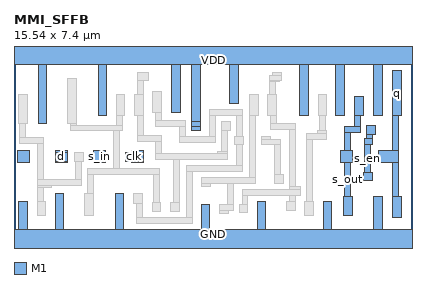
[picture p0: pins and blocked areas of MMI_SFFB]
MACRO MMI_SFFB
	CLASS CORE ;
	FOREIGN MMI_SFFB 0 0 ;
	SIZE 15.54 BY 7.4 ;
	SYMMETRY X Y ;
	SITE CORE1 ;
	PIN d
		DIRECTION input ;
		USE SIGNAL ;
		PORT
			LAYER M1 ;
			RECT 1.625 3.485 2.075 3.555 ;
			LAYER M1 ;
			RECT 1.61 3.145 2.075 3.485 ;
			LAYER M1 ;
			RECT 1.625 3.105 2.075 3.145 ;
		END
		AntennaGateArea 0.4968 ;
	END d
	PIN GND
		DIRECTION inout ;
		USE GROUND ;
		PORT
			LAYER M1 ;
			RECT 0.18 0.5 0.52 1.57 ;
			LAYER M1 ;
			RECT 1.6 0.5 1.94 1.88 ;
			LAYER M1 ;
			RECT 3.94 0.5 4.28 1.88 ;
			LAYER M1 ;
			RECT 7.29 0.5 7.63 1.48 ;
			LAYER M1 ;
			RECT 9.47 0.5 9.81 1.57 ;
			LAYER M1 ;
			RECT 12.04 0.5 12.38 1.57 ;
			LAYER M1 ;
			RECT 14.02 0.5 14.36 1.79 ;
			LAYER M1 ;
			RECT 0 -0.5 15.54 0.5 ;
		END
	END GND
	PIN q
		DIRECTION output ;
		USE SIGNAL ;
		PORT
			LAYER M1 ;
			RECT 14.74 4.91 15.08 6.67 ;
			LAYER M1 ;
			RECT 14.74 3.555 14.97 4.91 ;
			LAYER M1 ;
			RECT 14.205 3.105 14.97 3.555 ;
			LAYER M1 ;
			RECT 14.74 1.79 14.97 3.105 ;
			LAYER M1 ;
			RECT 14.74 0.95 15.08 1.79 ;
		END
		AntennaDiffArea 1.3248 ;
	END q
	PIN s_in
		DIRECTION input ;
		USE SIGNAL ;
		PORT
			LAYER M1 ;
			RECT 3.105 3.105 3.555 3.555 ;
		END
		AntennaGateArea 0.2484 ;
	END s_in
	PIN s_en
		DIRECTION input ;
		USE SIGNAL ;
		PORT
			LAYER M1 ;
			RECT 13.74 4.18 14.08 4.52 ;
			LAYER M1 ;
			RECT 13.74 4.02 13.97 4.18 ;
			LAYER M1 ;
			RECT 13.66 3.79 13.97 4.02 ;
			LAYER M1 ;
			RECT 0.145 3.105 0.595 3.555 ;
			LAYER M1 ;
			RECT 13.66 2.72 13.89 3.79 ;
			LAYER M1 ;
			RECT 13.62 2.38 13.96 2.72 ;
		END
		AntennaGateArea 1.0404 ;
	END s_en
	PIN VDD
		DIRECTION inout ;
		USE POWER ;
		PORT
			LAYER M1 ;
			RECT 0 6.9 15.54 7.9 ;
			LAYER M1 ;
			RECT 0.94 4.61 1.28 6.9 ;
			LAYER M1 ;
			RECT 3.28 4.91 3.62 6.9 ;
			LAYER M1 ;
			RECT 6.13 5.03 6.47 6.9 ;
			LAYER M1 ;
			RECT 6.925 4.69 7.265 6.9 ;
			LAYER M1 ;
			RECT 8.405 5.38 8.745 6.9 ;
			LAYER M1 ;
			RECT 11.12 4.91 11.46 6.9 ;
			LAYER M1 ;
			RECT 12.54 4.91 12.88 6.9 ;
			LAYER M1 ;
			RECT 14.02 4.91 14.36 6.9 ;
			LAYER M1 ;
			RECT 6.925 4.515 7.27 4.69 ;
			LAYER M1 ;
			RECT 6.93 4.35 7.27 4.515 ;
		END
	END VDD
	PIN s_out
		DIRECTION output ;
		USE SIGNAL ;
		PORT
			LAYER M1 ;
			RECT 13.26 4.91 13.6 5.67 ;
			LAYER M1 ;
			RECT 13.26 4.495 13.49 4.91 ;
			LAYER M1 ;
			RECT 12.865 4.265 13.49 4.495 ;
			LAYER M1 ;
			RECT 12.865 3.555 13.095 4.265 ;
			LAYER M1 ;
			RECT 12.725 3.105 13.175 3.555 ;
			LAYER M1 ;
			RECT 12.865 1.79 13.095 3.105 ;
			LAYER M1 ;
			RECT 12.83 1.03 13.17 1.79 ;
		END
		AntennaDiffArea 0.8568 ;
	END s_out
	PIN clk
		DIRECTION input ;
		USE CLOCK ;
		PORT
			LAYER M1 ;
			RECT 4.585 3.49 5.035 3.555 ;
			LAYER M1 ;
			RECT 4.34 3.15 5.035 3.49 ;
			LAYER M1 ;
			RECT 4.585 3.105 5.035 3.15 ;
		END
		AntennaGateArea 0.6408 ;
	END clk
	OBS
		LAYER M1 ;
		RECT 0.18 4.61 0.52 5.73 ;
		LAYER M1 ;
		RECT 2.09 4.61 2.43 6.37 ;
		LAYER M1 ;
		RECT 4.81 6.275 5.23 6.615 ;
		LAYER M1 ;
		RECT 4.81 5.75 5.04 6.275 ;
		LAYER M1 ;
		RECT 3.98 4.91 4.32 5.75 ;
		LAYER M1 ;
		RECT 4.7 4.91 5.04 5.75 ;
		LAYER M1 ;
		RECT 5.41 5.03 5.75 5.87 ;
		LAYER M1 ;
		RECT 0.215 4.07 0.445 4.61 ;
		LAYER M1 ;
		RECT 2.2 4.555 2.43 4.61 ;
		LAYER M1 ;
		RECT 3.98 4.555 4.21 4.91 ;
		LAYER M1 ;
		RECT 2.2 4.325 4.21 4.555 ;
		LAYER M1 ;
		RECT 0.215 3.84 1.13 4.07 ;
		LAYER M1 ;
		RECT 0.9 2.45 1.13 3.84 ;
		LAYER M1 ;
		RECT 2.37 3.145 2.71 3.485 ;
		LAYER M1 ;
		RECT 2.38 2.45 2.61 3.145 ;
		LAYER M1 ;
		RECT 3.865 2.875 4.095 4.325 ;
		LAYER M1 ;
		RECT 4.81 4.14 5.04 4.91 ;
		LAYER M1 ;
		RECT 5.52 4.73 5.75 5.03 ;
		LAYER M1 ;
		RECT 5.52 4.5 6.68 4.73 ;
		LAYER M1 ;
		RECT 10.08 6.475 10.42 6.62 ;
		LAYER M1 ;
		RECT 9.955 6.28 10.42 6.475 ;
		LAYER M1 ;
		RECT 9.955 6.245 10.35 6.28 ;
		LAYER M1 ;
		RECT 9.955 5.75 10.185 6.245 ;
		LAYER M1 ;
		RECT 7.61 4.92 8.88 5.15 ;
		LAYER M1 ;
		RECT 4.81 3.91 5.73 4.14 ;
		LAYER M1 ;
		RECT 5.5 3.43 5.73 3.91 ;
		LAYER M1 ;
		RECT 6.45 4.12 6.68 4.5 ;
		LAYER M1 ;
		RECT 7.61 4.12 7.84 4.92 ;
		LAYER M1 ;
		RECT 6.45 3.89 7.84 4.12 ;
		LAYER M1 ;
		RECT 8.08 4.35 8.42 4.69 ;
		LAYER M1 ;
		RECT 8.08 3.54 8.31 4.35 ;
		LAYER M1 ;
		RECT 8.65 4.12 8.88 4.92 ;
		LAYER M1 ;
		RECT 9.17 4.91 9.51 5.75 ;
		LAYER M1 ;
		RECT 9.89 4.91 10.23 5.75 ;
		LAYER M1 ;
		RECT 11.84 4.91 12.18 5.75 ;
		LAYER M1 ;
		RECT 8.6 3.78 8.94 4.12 ;
		LAYER M1 ;
		RECT 7.93 3.43 8.31 3.54 ;
		LAYER M1 ;
		RECT 5.5 3.2 8.31 3.43 ;
		LAYER M1 ;
		RECT 0.9 2.22 2.61 2.45 ;
		LAYER M1 ;
		RECT 2.86 2.645 5.65 2.875 ;
		LAYER M1 ;
		RECT 0.9 2.11 1.455 2.22 ;
		LAYER M1 ;
		RECT 0.9 1.57 1.13 2.11 ;
		LAYER M1 ;
		RECT 2.86 1.88 3.09 2.645 ;
		LAYER M1 ;
		RECT 0.9 1.05 1.24 1.57 ;
		LAYER M1 ;
		RECT 2.75 1.04 3.09 1.88 ;
		LAYER M1 ;
		RECT 4.66 1.5 5 1.88 ;
		LAYER M1 ;
		RECT 5.42 1.53 5.65 2.645 ;
		LAYER M1 ;
		RECT 6.21 1.53 6.44 3.2 ;
		LAYER M1 ;
		RECT 8.65 2.97 8.88 3.78 ;
		LAYER M1 ;
		RECT 4.77 0.96 5 1.5 ;
		LAYER M1 ;
		RECT 5.38 1.19 5.72 1.53 ;
		LAYER M1 ;
		RECT 6.1 1.19 6.44 1.53 ;
		LAYER M1 ;
		RECT 6.73 2.74 8.88 2.97 ;
		LAYER M1 ;
		RECT 6.73 0.96 6.96 2.74 ;
		LAYER M1 ;
		RECT 9.17 2.5 9.4 4.91 ;
		LAYER M1 ;
		RECT 10 4.6 10.23 4.91 ;
		LAYER M1 ;
		RECT 10 4.37 10.96 4.6 ;
		LAYER M1 ;
		RECT 9.65 4.01 9.99 4.12 ;
		LAYER M1 ;
		RECT 9.65 3.78 10.37 4.01 ;
		LAYER M1 ;
		RECT 7.32 2.27 9.4 2.5 ;
		LAYER M1 ;
		RECT 10.14 2.61 10.37 3.78 ;
		LAYER M1 ;
		RECT 10.14 2.27 10.48 2.61 ;
		LAYER M1 ;
		RECT 7.32 2.16 7.66 2.27 ;
		LAYER M1 ;
		RECT 8.31 1.48 8.54 2.27 ;
		LAYER M1 ;
		RECT 10.73 2.15 10.96 4.37 ;
		LAYER M1 ;
		RECT 11.89 4.325 12.12 4.91 ;
		LAYER M1 ;
		RECT 11.835 4.215 12.175 4.325 ;
		LAYER M1 ;
		RECT 11.405 3.985 12.175 4.215 ;
		LAYER M1 ;
		RECT 10.73 2.04 11.15 2.15 ;
		LAYER M1 ;
		RECT 8.88 1.81 11.15 2.04 ;
		LAYER M1 ;
		RECT 8.88 1.48 9.11 1.81 ;
		LAYER M1 ;
		RECT 10.73 1.57 10.96 1.81 ;
		LAYER M1 ;
		RECT 11.405 1.57 11.635 3.985 ;
		LAYER M1 ;
		RECT 4.77 0.73 6.96 0.96 ;
		LAYER M1 ;
		RECT 8.01 1.24 8.54 1.48 ;
		LAYER M1 ;
		RECT 8.01 1.1 8.35 1.24 ;
		LAYER M1 ;
		RECT 8.77 1.14 9.11 1.48 ;
		LAYER M1 ;
		RECT 10.62 1.23 10.96 1.57 ;
		LAYER M1 ;
		RECT 11.32 1.03 11.66 1.57 ;
	END
END MMI_SFFB
